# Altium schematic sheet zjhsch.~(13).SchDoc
size A4

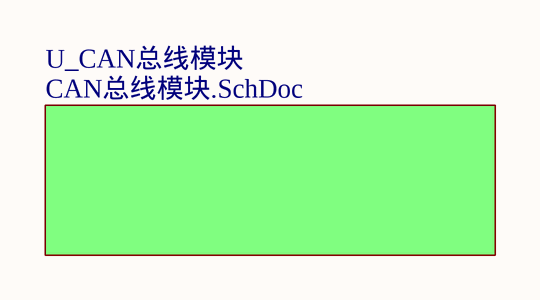
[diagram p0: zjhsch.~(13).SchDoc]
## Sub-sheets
U_CAN总线模块 = CAN总线模块.SchDoc: no entries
